VERSION 5.7 ;
  NOWIREEXTENSIONATPIN ON ;
  DIVIDERCHAR "/" ;
  BUSBITCHARS "[]" ;
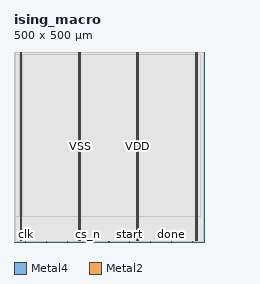
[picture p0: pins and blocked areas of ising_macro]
MACRO ising_macro
  CLASS BLOCK ;
  FOREIGN ising_macro ;
  ORIGIN 0.000 0.000 ;
  SIZE 500.000 BY 500.000 ;
  PIN VDD
    DIRECTION INOUT ;
    USE POWER ;
    PORT
      LAYER Metal4 ;
        RECT 16.080 3.620 17.680 498.140 ;
    END
    PORT
      LAYER Metal4 ;
        RECT 169.680 3.620 171.280 498.140 ;
    END
    PORT
      LAYER Metal4 ;
        RECT 323.280 3.620 324.880 498.140 ;
    END
    PORT
      LAYER Metal4 ;
        RECT 476.880 3.620 478.480 498.140 ;
    END
  END VDD
  PIN VSS
    DIRECTION INOUT ;
    USE GROUND ;
    PORT
      LAYER Metal4 ;
        RECT 19.380 3.620 20.980 498.140 ;
    END
    PORT
      LAYER Metal4 ;
        RECT 172.980 3.620 174.580 498.140 ;
    END
    PORT
      LAYER Metal4 ;
        RECT 326.580 3.620 328.180 498.140 ;
    END
    PORT
      LAYER Metal4 ;
        RECT 480.180 3.620 481.780 498.140 ;
    END
  END VSS
  PIN clk
    DIRECTION INPUT ;
    USE SIGNAL ;
    ANTENNAGATEAREA 4.738000 ;
    PORT
      LAYER Metal2 ;
        RECT 30.240 0.000 30.800 0.560 ;
    END
  END clk
  PIN cs_n
    DIRECTION INPUT ;
    USE SIGNAL ;
    ANTENNAGATEAREA 0.498500 ;
    PORT
      LAYER Metal2 ;
        RECT 194.880 0.000 195.440 0.560 ;
    END
  END cs_n
  PIN done
    DIRECTION OUTPUT ;
    USE SIGNAL ;
    ANTENNADIFFAREA 0.897600 ;
    PORT
      LAYER Metal2 ;
        RECT 414.400 0.000 414.960 0.560 ;
    END
  END done
  PIN rst_n
    DIRECTION INPUT ;
    USE SIGNAL ;
    ANTENNAGATEAREA 0.498500 ;
    PORT
      LAYER Metal2 ;
        RECT 85.120 0.000 85.680 0.560 ;
    END
  END rst_n
  PIN sclk
    DIRECTION INPUT ;
    USE SIGNAL ;
    ANTENNAGATEAREA 0.498500 ;
    PORT
      LAYER Metal2 ;
        RECT 140.000 0.000 140.560 0.560 ;
    END
  END sclk
  PIN sdi
    DIRECTION INPUT ;
    USE SIGNAL ;
    ANTENNAGATEAREA 0.498500 ;
    PORT
      LAYER Metal2 ;
        RECT 249.760 0.000 250.320 0.560 ;
    END
  END sdi
  PIN sdo
    DIRECTION OUTPUT ;
    USE SIGNAL ;
    ANTENNADIFFAREA 0.897600 ;
    PORT
      LAYER Metal2 ;
        RECT 359.520 0.000 360.080 0.560 ;
    END
  END sdo
  PIN start
    DIRECTION INPUT ;
    USE SIGNAL ;
    ANTENNAGATEAREA 0.498500 ;
    PORT
      LAYER Metal2 ;
        RECT 304.640 0.000 305.200 0.560 ;
    END
  END start
  PIN trng_raw
    DIRECTION OUTPUT ;
    USE SIGNAL ;
    ANTENNADIFFAREA 0.897600 ;
    PORT
      LAYER Metal2 ;
        RECT 469.280 0.000 469.840 0.560 ;
    END
  END trng_raw
  OBS
      LAYER Pwell ;
        RECT 0.130 496.080 499.390 498.270 ;
      LAYER Nwell ;
        RECT 0.130 491.760 499.390 496.080 ;
      LAYER Pwell ;
        RECT 0.130 488.240 499.390 491.760 ;
      LAYER Nwell ;
        RECT 0.130 483.920 499.390 488.240 ;
      LAYER Pwell ;
        RECT 0.130 480.400 499.390 483.920 ;
      LAYER Nwell ;
        RECT 0.130 476.080 499.390 480.400 ;
      LAYER Pwell ;
        RECT 0.130 472.560 499.390 476.080 ;
      LAYER Nwell ;
        RECT 0.130 468.240 499.390 472.560 ;
      LAYER Pwell ;
        RECT 0.130 464.720 499.390 468.240 ;
      LAYER Nwell ;
        RECT 0.130 460.400 499.390 464.720 ;
      LAYER Pwell ;
        RECT 0.130 456.880 499.390 460.400 ;
      LAYER Nwell ;
        RECT 0.130 452.560 499.390 456.880 ;
      LAYER Pwell ;
        RECT 0.130 449.040 499.390 452.560 ;
      LAYER Nwell ;
        RECT 0.130 444.720 499.390 449.040 ;
      LAYER Pwell ;
        RECT 0.130 441.200 499.390 444.720 ;
      LAYER Nwell ;
        RECT 0.130 436.880 499.390 441.200 ;
      LAYER Pwell ;
        RECT 0.130 433.360 499.390 436.880 ;
      LAYER Nwell ;
        RECT 0.130 429.040 499.390 433.360 ;
      LAYER Pwell ;
        RECT 0.130 425.520 499.390 429.040 ;
      LAYER Nwell ;
        RECT 0.130 421.200 499.390 425.520 ;
      LAYER Pwell ;
        RECT 0.130 417.680 499.390 421.200 ;
      LAYER Nwell ;
        RECT 0.130 413.360 499.390 417.680 ;
      LAYER Pwell ;
        RECT 0.130 409.840 499.390 413.360 ;
      LAYER Nwell ;
        RECT 0.130 405.520 499.390 409.840 ;
      LAYER Pwell ;
        RECT 0.130 402.000 499.390 405.520 ;
      LAYER Nwell ;
        RECT 0.130 397.680 499.390 402.000 ;
      LAYER Pwell ;
        RECT 0.130 394.160 499.390 397.680 ;
      LAYER Nwell ;
        RECT 0.130 389.840 499.390 394.160 ;
      LAYER Pwell ;
        RECT 0.130 386.320 499.390 389.840 ;
      LAYER Nwell ;
        RECT 0.130 382.000 499.390 386.320 ;
      LAYER Pwell ;
        RECT 0.130 378.480 499.390 382.000 ;
      LAYER Nwell ;
        RECT 0.130 374.160 499.390 378.480 ;
      LAYER Pwell ;
        RECT 0.130 370.640 499.390 374.160 ;
      LAYER Nwell ;
        RECT 0.130 366.320 499.390 370.640 ;
      LAYER Pwell ;
        RECT 0.130 362.800 499.390 366.320 ;
      LAYER Nwell ;
        RECT 0.130 358.480 499.390 362.800 ;
      LAYER Pwell ;
        RECT 0.130 354.960 499.390 358.480 ;
      LAYER Nwell ;
        RECT 0.130 350.640 499.390 354.960 ;
      LAYER Pwell ;
        RECT 0.130 347.120 499.390 350.640 ;
      LAYER Nwell ;
        RECT 0.130 342.800 499.390 347.120 ;
      LAYER Pwell ;
        RECT 0.130 339.280 499.390 342.800 ;
      LAYER Nwell ;
        RECT 0.130 334.960 499.390 339.280 ;
      LAYER Pwell ;
        RECT 0.130 331.440 499.390 334.960 ;
      LAYER Nwell ;
        RECT 0.130 327.120 499.390 331.440 ;
      LAYER Pwell ;
        RECT 0.130 323.600 499.390 327.120 ;
      LAYER Nwell ;
        RECT 0.130 319.280 499.390 323.600 ;
      LAYER Pwell ;
        RECT 0.130 315.760 499.390 319.280 ;
      LAYER Nwell ;
        RECT 0.130 311.440 499.390 315.760 ;
      LAYER Pwell ;
        RECT 0.130 307.920 499.390 311.440 ;
      LAYER Nwell ;
        RECT 0.130 303.600 499.390 307.920 ;
      LAYER Pwell ;
        RECT 0.130 300.080 499.390 303.600 ;
      LAYER Nwell ;
        RECT 0.130 295.760 499.390 300.080 ;
      LAYER Pwell ;
        RECT 0.130 292.240 499.390 295.760 ;
      LAYER Nwell ;
        RECT 0.130 287.920 499.390 292.240 ;
      LAYER Pwell ;
        RECT 0.130 284.400 499.390 287.920 ;
      LAYER Nwell ;
        RECT 0.130 280.080 499.390 284.400 ;
      LAYER Pwell ;
        RECT 0.130 276.560 499.390 280.080 ;
      LAYER Nwell ;
        RECT 0.130 272.240 499.390 276.560 ;
      LAYER Pwell ;
        RECT 0.130 268.720 499.390 272.240 ;
      LAYER Nwell ;
        RECT 0.130 264.400 499.390 268.720 ;
      LAYER Pwell ;
        RECT 0.130 260.880 499.390 264.400 ;
      LAYER Nwell ;
        RECT 0.130 256.560 499.390 260.880 ;
      LAYER Pwell ;
        RECT 0.130 253.040 499.390 256.560 ;
      LAYER Nwell ;
        RECT 0.130 248.720 499.390 253.040 ;
      LAYER Pwell ;
        RECT 0.130 245.200 499.390 248.720 ;
      LAYER Nwell ;
        RECT 0.130 240.880 499.390 245.200 ;
      LAYER Pwell ;
        RECT 0.130 237.360 499.390 240.880 ;
      LAYER Nwell ;
        RECT 0.130 233.040 499.390 237.360 ;
      LAYER Pwell ;
        RECT 0.130 229.520 499.390 233.040 ;
      LAYER Nwell ;
        RECT 0.130 225.200 499.390 229.520 ;
      LAYER Pwell ;
        RECT 0.130 221.680 499.390 225.200 ;
      LAYER Nwell ;
        RECT 0.130 217.360 499.390 221.680 ;
      LAYER Pwell ;
        RECT 0.130 213.840 499.390 217.360 ;
      LAYER Nwell ;
        RECT 0.130 209.520 499.390 213.840 ;
      LAYER Pwell ;
        RECT 0.130 206.000 499.390 209.520 ;
      LAYER Nwell ;
        RECT 0.130 201.680 499.390 206.000 ;
      LAYER Pwell ;
        RECT 0.130 198.160 499.390 201.680 ;
      LAYER Nwell ;
        RECT 0.130 193.840 499.390 198.160 ;
      LAYER Pwell ;
        RECT 0.130 190.320 499.390 193.840 ;
      LAYER Nwell ;
        RECT 0.130 186.000 499.390 190.320 ;
      LAYER Pwell ;
        RECT 0.130 182.480 499.390 186.000 ;
      LAYER Nwell ;
        RECT 0.130 178.160 499.390 182.480 ;
      LAYER Pwell ;
        RECT 0.130 174.640 499.390 178.160 ;
      LAYER Nwell ;
        RECT 0.130 170.320 499.390 174.640 ;
      LAYER Pwell ;
        RECT 0.130 166.800 499.390 170.320 ;
      LAYER Nwell ;
        RECT 0.130 162.480 499.390 166.800 ;
      LAYER Pwell ;
        RECT 0.130 158.960 499.390 162.480 ;
      LAYER Nwell ;
        RECT 0.130 154.640 499.390 158.960 ;
      LAYER Pwell ;
        RECT 0.130 151.120 499.390 154.640 ;
      LAYER Nwell ;
        RECT 0.130 146.800 499.390 151.120 ;
      LAYER Pwell ;
        RECT 0.130 143.280 499.390 146.800 ;
      LAYER Nwell ;
        RECT 0.130 138.960 499.390 143.280 ;
      LAYER Pwell ;
        RECT 0.130 135.440 499.390 138.960 ;
      LAYER Nwell ;
        RECT 0.130 131.120 499.390 135.440 ;
      LAYER Pwell ;
        RECT 0.130 127.600 499.390 131.120 ;
      LAYER Nwell ;
        RECT 0.130 123.280 499.390 127.600 ;
      LAYER Pwell ;
        RECT 0.130 119.760 499.390 123.280 ;
      LAYER Nwell ;
        RECT 0.130 115.440 499.390 119.760 ;
      LAYER Pwell ;
        RECT 0.130 111.920 499.390 115.440 ;
      LAYER Nwell ;
        RECT 0.130 107.600 499.390 111.920 ;
      LAYER Pwell ;
        RECT 0.130 104.080 499.390 107.600 ;
      LAYER Nwell ;
        RECT 0.130 99.760 499.390 104.080 ;
      LAYER Pwell ;
        RECT 0.130 96.240 499.390 99.760 ;
      LAYER Nwell ;
        RECT 0.130 91.920 499.390 96.240 ;
      LAYER Pwell ;
        RECT 0.130 88.400 499.390 91.920 ;
      LAYER Nwell ;
        RECT 0.130 84.080 499.390 88.400 ;
      LAYER Pwell ;
        RECT 0.130 80.560 499.390 84.080 ;
      LAYER Nwell ;
        RECT 0.130 76.240 499.390 80.560 ;
      LAYER Pwell ;
        RECT 0.130 72.720 499.390 76.240 ;
      LAYER Nwell ;
        RECT 0.130 68.400 499.390 72.720 ;
      LAYER Pwell ;
        RECT 0.130 64.880 499.390 68.400 ;
      LAYER Nwell ;
        RECT 0.130 60.560 499.390 64.880 ;
      LAYER Pwell ;
        RECT 0.130 57.040 499.390 60.560 ;
      LAYER Nwell ;
        RECT 0.130 52.720 499.390 57.040 ;
      LAYER Pwell ;
        RECT 0.130 49.200 499.390 52.720 ;
      LAYER Nwell ;
        RECT 0.130 44.880 499.390 49.200 ;
      LAYER Pwell ;
        RECT 0.130 41.360 499.390 44.880 ;
      LAYER Nwell ;
        RECT 0.130 37.040 499.390 41.360 ;
      LAYER Pwell ;
        RECT 0.130 33.520 499.390 37.040 ;
      LAYER Nwell ;
        RECT 0.130 29.200 499.390 33.520 ;
      LAYER Pwell ;
        RECT 0.130 25.680 499.390 29.200 ;
      LAYER Nwell ;
        RECT 0.130 21.360 499.390 25.680 ;
      LAYER Pwell ;
        RECT 0.130 17.840 499.390 21.360 ;
      LAYER Nwell ;
        RECT 0.130 13.520 499.390 17.840 ;
      LAYER Pwell ;
        RECT 0.130 10.000 499.390 13.520 ;
      LAYER Nwell ;
        RECT 0.130 5.680 499.390 10.000 ;
      LAYER Pwell ;
        RECT 0.130 3.490 499.390 5.680 ;
      LAYER Metal1 ;
        RECT 0.560 3.620 498.960 498.140 ;
      LAYER Metal2 ;
        RECT 2.380 0.860 497.700 498.030 ;
        RECT 2.380 0.090 29.940 0.860 ;
        RECT 31.100 0.090 84.820 0.860 ;
        RECT 85.980 0.090 139.700 0.860 ;
        RECT 140.860 0.090 194.580 0.860 ;
        RECT 195.740 0.090 249.460 0.860 ;
        RECT 250.620 0.090 304.340 0.860 ;
        RECT 305.500 0.090 359.220 0.860 ;
        RECT 360.380 0.090 414.100 0.860 ;
        RECT 415.260 0.090 468.980 0.860 ;
        RECT 470.140 0.090 497.700 0.860 ;
      LAYER Metal3 ;
        RECT 2.890 0.140 497.750 497.980 ;
      LAYER Metal4 ;
        RECT 4.060 67.290 15.780 492.710 ;
        RECT 17.980 67.290 19.080 492.710 ;
        RECT 21.280 67.290 169.380 492.710 ;
        RECT 171.580 67.290 172.680 492.710 ;
        RECT 174.880 67.290 322.980 492.710 ;
        RECT 325.180 67.290 326.280 492.710 ;
        RECT 328.480 67.290 476.580 492.710 ;
        RECT 478.780 67.290 479.880 492.710 ;
        RECT 482.080 67.290 490.420 492.710 ;
  END
END ising_macro
END LIBRARY

